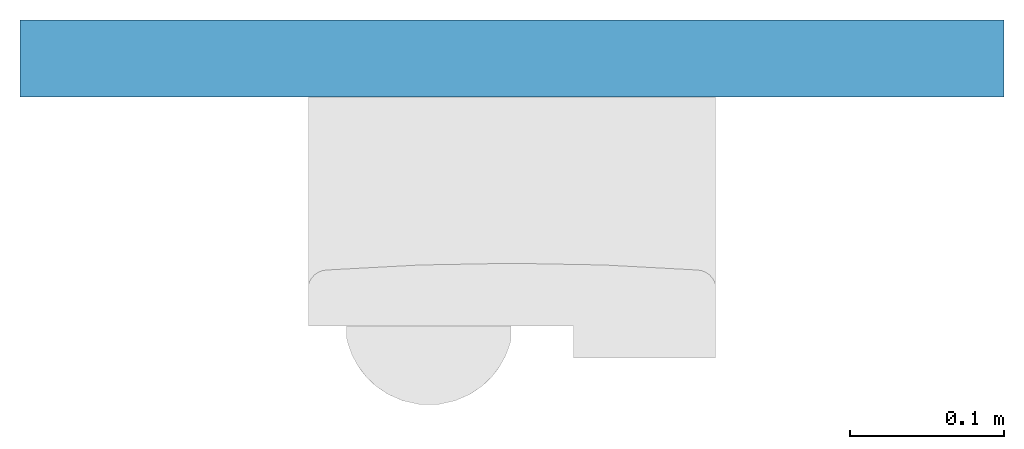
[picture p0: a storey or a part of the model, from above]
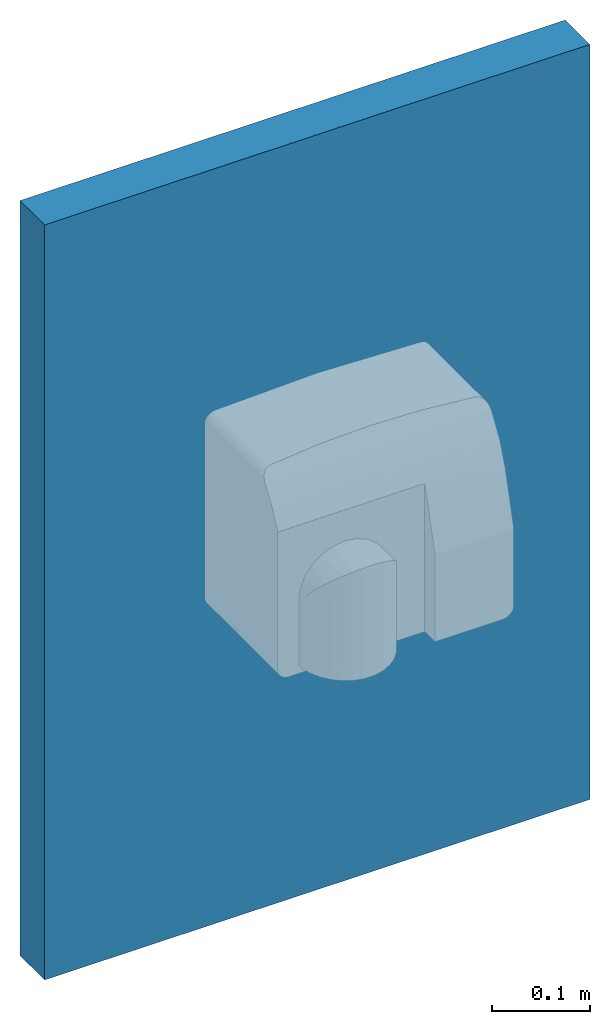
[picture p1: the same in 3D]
Properties of the parts of a building model (IFC2X3)

# File
Description: ViewDefinition [CoordinationView]
Time: 2017-12-13T17:22:41
Written by: The EXPRESS Data Manager Version 5.01.0100.02.64mod : 6 Jun 2012
Made in: 20140709_2115(x64) - Exporter 2014.0.2014.0709 - Default UI
Comment: STEP Physical File produced by: The EXPRESS Data Manager Version 5.01.0100.02.64mod : 6 Jun 2012 * Module: EDMstepFileFactory/EDMstandAlone * Creation date: Wed Dec 13 17:22:41 2017 * Host: BIM-HP * Database: C:\Users\dcole\AppData\Local\Temp\{E35F8B0E-3796-4B30-98A9-D8B8D147AE8A}\ifc * Database version: 5507 * Database creation date: Wed Dec 13 17:22:40 2017 * Schema: IFC2X3 * Model: DataRepository.ifc * Model creation date: Wed Dec 13 17:22:40 2017 * Header model: DataRepository.ifc_HeaderModel * Header model creation date: Wed Dec 13 17:22:41 2017 * EDMuser: sdai-user * EDMgroup: sdai-group * License ID and type: 5605 : Permanent license. Expiry date: * EDMstepFileFactory options: 020000

# IfcProject
LongName: P:\Fastrack\53721_DOLPHIN SOLUTIONS LIMITED\ADDITIONAL DRAWINGS 2017 BIM\IFC\DRYER UPDATES\BC230W.ifc

# IfcSite, Default
RefLatitude: 42, 24, 53, 508911; RefLongitude: -71, -15, -29, -58837; RefElevation: 0 mm

# IfcBuilding
Pset_BuildingCommon - NumberOfStoreys: 1

# IfcBuildingStorey, Level 1
LongName: Level 1; Elevation: 0 mm
Graphics - Symbol at End 1 Default: no; Symbol at End 2 Default: yes; Line Pattern: -3000010; Color: 0; Line Weight: 1
Constraints - Elevation: 0 mm; Elevation Base: Project Base Point
Identity Data - Structural: no; Building Story: yes; Name: Level 1
Dimensions - Computation Height: 0 mm

# IfcBuildingElementProxy: BC230W Dolphin White Metal Hand Dryer, BC230W:BC230W Dolphin White Metal Hand Dryer:58177
In: Level 1
Material: Nozzle, Glass, White Metal
Constraints - Host: Level : Level 1; Level: Level: Level 1; Offset: 396.767 mm
Electrical - Circuiting - Electrical Data: 240 V/1-0 VA
Identity Data - Mark: 3; Assembly Code: D5090900; URL: www.dolphinsolutions.co.uk; Manufacturer: Dolphin Solutions Limited; OmniClass Title: Distribution Boards and Control Panels; Email: info@dolphinsolutions.co.uk; Address: Southpoint, Compass Park, Junction Road, Bodiam, TN32 5BS; Model: BC230W; Assembly Description: Misc. Other Electrical Systems; Description: White plated hand dryer; Fax No.: +44 (0) 1424 205200; Tel No.: +44 (0) 1424 202224; OmniClass Number: 23.80.30.11.17
Phasing - Phase Created: New Construction
Pset_ManufacturerTypeInformation - Manufacturer: Dolphin Solutions Limited
Pset_BuildingElementProxyCommon - Reference: BC230W Dolphin White Metal Hand Dryer
Dimensions - Height: 245mm; Width: 265mm; Height above counter: The unit should be minimum 300mm above the surface below.; Projection: 200mm
General - Product Data: Infra-red sensor - no touch. Rated power: 2500w (10.8A). IPX1 rated. Class 1 rated isolation. Airspeed: 30 m/s. Sound level: 85 +/- 3 db. 360 deg revolving nozzle. Durable metal construction - vandal resistant. Voltage: 220/240 (50Hz). Air movement volume: 270m3/hour. 2 year manufacturer's warranty. Timing protection - 60 seconds auto shut off. Approximately 20-25 second dry time. Unit should be mounted to give no less than 300mm clearance from the bottom of the unit to the nearest surface below.; Product Page Link: https://www.dolphinsolutions.co.uk/product/white-metal-hand-dryer/
Electrical - Rated Power: 2500w (10.8A)

# IfcWallStandardCase: Basic Wall:Wall 1, Basic Wall:Wall 1:3092
In: Level 1
Type - PredefinedType: STANDARD; Material: Default Wall 50 mm
Type - Construction - Width: 50 mm; Wrapping at Inserts: Do not wrap; Function: Exterior
Type - Analytical Properties - Roughness: 1; Absorptance: 0.1
Type - Graphics - Coarse Scale Fill Color: 8454143
Constraints - Top Extension Distance: 0 mm; Room Bounding: yes; Top is Attached: no; Base is Attached: no; Base Constraint: Level: Level 1; Unconnected Height: 936.967 mm; Base Extension Distance: 0 mm; Base Offset: 0 mm; Related to Mass: no; Location Line: Finish Face: Interior; Top Offset: 0 mm
Structural - Structural Usage: Non-bearing; Structural: no; Enable Analytical Model: no
Dimensions - Area: 0.599659 m2; Length: 640 mm; Volume: 0.0299829 m3
Phasing - Phase Created: New Construction
Pset_WallCommon - Reference: Wall 1; LoadBearing: no; ExtendToStructure: no; IsExternal: yes
